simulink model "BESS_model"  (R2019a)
settings: Solver=VariableStepAuto  StartTime=0.0  StopTime=3600*24*3  FixedStep=1  RelTol=1e-3

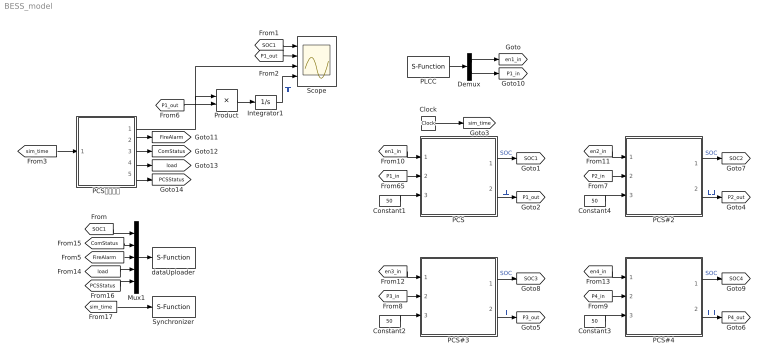
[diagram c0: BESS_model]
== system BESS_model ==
  Clock : Clock
  Constant1 : Constant  Value=50
  Constant2 : Constant  Commented=on  Value=50
  Constant3 : Constant  Commented=on  Value=50
  Constant4 : Constant  Commented=on  Value=50
  Demux : Demux  Outputs=2
  Integrator1 : Integrator
  Mux1 : Mux  Inputs=5
  PCS : Subsystem
  PCS#2 : Subsystem  Commented=on
  PCS#3 : Subsystem  Commented=on
  PCS#4 : Subsystem  Commented=on
  PCS数据生成 : Subsystem
  PLCC : S-Function  FunctionName=modbusCom  SFunctionDeploymentMode=off  EnableBusSupport=off
  Product : Product
  Scope : Scope  NumInputPorts=4
  Synchronizer : S-Function  FunctionName=Synchronizer  SFunctionDeploymentMode=off  EnableBusSupport=off
  dataUploader : S-Function  FunctionName=pcsUpdate  SFunctionDeploymentMode=off  EnableBusSupport=off
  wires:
  [P1_in] -> PCS/2(下发给PCS的遥调)
  Mux1/1 -> dataUploader/1
  PCS/1(SOC) -> [SOC1]  "SOC"
  PCS/2(实际功率) -> [P1_out]  "功率"
  Constant1/1 -> PCS/3(SOC初始值)
  Clock/1 -> [sim_time]
  [P2_in] -> PCS#2/2(下发给PCS的遥调)
  [P3_in] -> PCS#3/2(下发给PCS的遥调)
  [P4_in] -> PCS#4/2(下发给PCS的遥调)
  Constant2/1 -> PCS#3/3(SOC初始值)
  Constant3/1 -> PCS#4/3(SOC初始值)
  Constant4/1 -> PCS#2/3(SOC初始值)
  PCS#2/2(实际功率) -> [P2_out]  "功率"
  PCS#3/2(实际功率) -> [P3_out]  "功率"
  PCS#4/2(实际功率) -> [P4_out]  "功率"
  PCS#2/1(SOC) -> [SOC2]  "SOC"
  PCS#3/1(SOC) -> [SOC3]  "SOC"
  PCS#4/1(SOC) -> [SOC4]  "SOC"
  [en1_in] -> PCS/1(下发给PMS的遥控)
  [en2_in] -> PCS#2/1(下发给PMS的遥控)
  [en3_in] -> PCS#3/1(下发给PMS的遥控)
  [en4_in] -> PCS#4/1(下发给PMS的遥控)
  [SOC1] -> Mux1/1
  PLCC/1 -> Demux/1
  [SOC1] -> Scope/1
  [P1_out] -> Scope/2
  Product/1 -> Integrator1/1
  Integrator1/1 -> Scope/4  "收益"
  [P1_out] -> Product/2
  [ComStatus] -> Mux1/2
  [FireAlarm] -> Mux1/3
  [load] -> Mux1/4
  [PCSStatus] -> Mux1/5
  [sim_time] -> Synchronizer/1
  [sim_time] -> PCS数据生成/1(仿真时间)
  PCS数据生成/2(消防状态) -> [FireAlarm]
  PCS数据生成/3(通信状态) -> [ComStatus]
  PCS数据生成/4(负载) -> [load]
  PCS数据生成/5(PCS状态) -> [PCSStatus]
  PCS数据生成/1(实时电价) -> Scope/3, Product/1
  Demux/1 -> [en1_in]
  Demux/2 -> [P1_in]

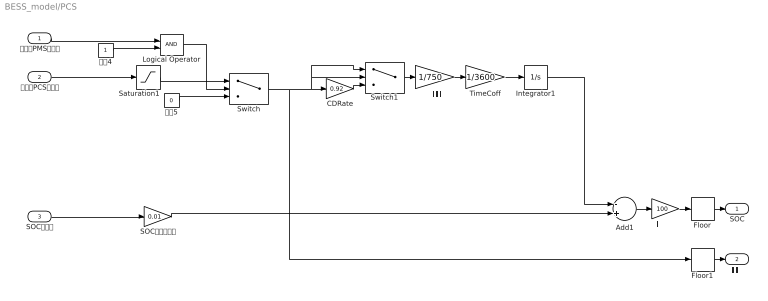
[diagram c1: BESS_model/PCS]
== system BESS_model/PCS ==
  下发给PMS的遥控 : Inport
  下发给PCS的遥调 : Inport  Port=2
  SOC初始值 : Inport  Port=3
  Add1 : Sum  Inputs=-+
  CDRate : Gain  Gain=0.92
  Floor : Rounding
  Floor1 : Rounding
  Integrator1 : Integrator  UpperSaturationLimit=0.5  LowerSaturationLimit=-0.5
  Logical Operator : Logic  AllPortsSameDT=off  OutDataTypeStr=boolean
  SOC转为百分数 : Gain  Gain=0.01
  Saturation1 : Saturate  UpperLimit=500  LowerLimit=-500
  Switch : Switch  Criteria=u2 ~= 0
  Switch1 : Switch  Criteria=u2 > Threshold
  TimeCoff : Gain  Gain=1/3600
  常数4 : Constant
  常数5 : Constant  Value=0
  蓄电池容量 : Gain  Gain=1/750
  转为整数 : Gain  Gain=100
  SOC : Outport  VectorParamsAs1DForOutWhenUnconnected=on
  实际功率 : Outport  Port=2  VectorParamsAs1DForOutWhenUnconnected=on
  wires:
  下发给PCS的遥调/1 -> Saturation1/1
  Switch1/1 -> 蓄电池容量/1
  常数4/1 -> Logical Operator/2
  Logical Operator/1 -> Switch/2
  常数5/1 -> Switch/3
  CDRate/1 -> Switch1/3
  蓄电池容量/1 -> TimeCoff/1
  Switch/1 -> CDRate/1, Switch1/1, Switch1/2, Floor1/1
  TimeCoff/1 -> Integrator1/1
  Integrator1/1 -> Add1/1
  Add1/1 -> 转为整数/1
  下发给PMS的遥控/1 -> Logical Operator/1
  Saturation1/1 -> Switch/1
  SOC初始值/1 -> SOC转为百分数/1
  SOC转为百分数/1 -> Add1/2
  转为整数/1 -> Floor/1
  Floor/1 -> SOC/1
  Floor1/1 -> 实际功率/1

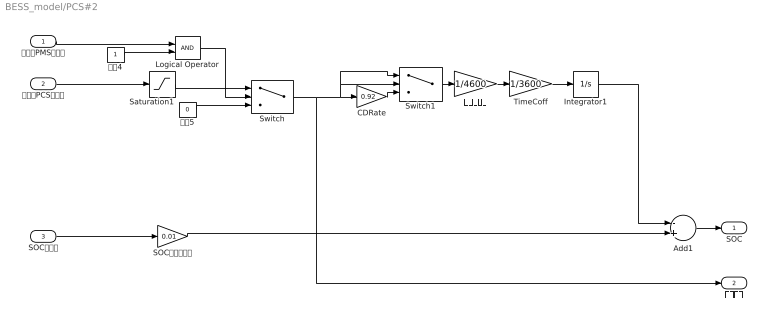
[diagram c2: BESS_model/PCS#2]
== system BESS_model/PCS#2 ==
  下发给PMS的遥控 : Inport
  下发给PCS的遥调 : Inport  Port=2
  SOC初始值 : Inport  Port=3
  Add1 : Sum  Inputs=-+
  CDRate : Gain  Gain=0.92
  Integrator1 : Integrator  UpperSaturationLimit=0.5  LowerSaturationLimit=-0.5
  Logical Operator : Logic  AllPortsSameDT=off  OutDataTypeStr=boolean
  SOC转为百分数 : Gain  Gain=0.01
  Saturation1 : Saturate  UpperLimit=2000  LowerLimit=-2000
  Switch : Switch  Criteria=u2 ~= 0
  Switch1 : Switch  Criteria=u2 > Threshold
  TimeCoff : Gain  Gain=1/3600
  常数4 : Constant
  常数5 : Constant  Value=0
  蓄电池容量 : Gain  Gain=1/4600
  SOC : Outport  VectorParamsAs1DForOutWhenUnconnected=on
  实际功率 : Outport  Port=2  VectorParamsAs1DForOutWhenUnconnected=on
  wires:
  SOC转为百分数/1 -> Add1/2
  SOC初始值/1 -> SOC转为百分数/1
  Saturation1/1 -> Switch/1
  下发给PMS的遥控/1 -> Logical Operator/1
  Add1/1 -> SOC/1
  Integrator1/1 -> Add1/1
  TimeCoff/1 -> Integrator1/1
  Switch/1 -> 实际功率/1, Switch1/2, Switch1/1, CDRate/1
  蓄电池容量/1 -> TimeCoff/1
  CDRate/1 -> Switch1/3
  常数5/1 -> Switch/3
  Logical Operator/1 -> Switch/2
  常数4/1 -> Logical Operator/2
  Switch1/1 -> 蓄电池容量/1
  下发给PCS的遥调/1 -> Saturation1/1

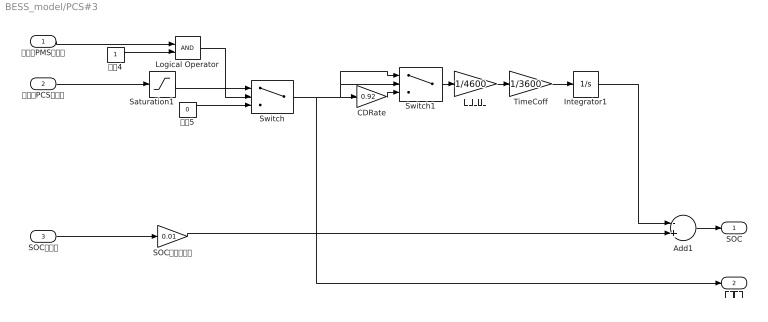
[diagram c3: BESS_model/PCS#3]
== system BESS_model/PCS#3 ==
  下发给PMS的遥控 : Inport
  下发给PCS的遥调 : Inport  Port=2
  SOC初始值 : Inport  Port=3
  Add1 : Sum  Inputs=-+
  CDRate : Gain  Gain=0.92
  Integrator1 : Integrator  UpperSaturationLimit=0.5  LowerSaturationLimit=-0.5
  Logical Operator : Logic  AllPortsSameDT=off  OutDataTypeStr=boolean
  SOC转为百分数 : Gain  Gain=0.01
  Saturation1 : Saturate  UpperLimit=2000  LowerLimit=-2000
  Switch : Switch  Criteria=u2 ~= 0
  Switch1 : Switch  Criteria=u2 > Threshold
  TimeCoff : Gain  Gain=1/3600
  常数4 : Constant
  常数5 : Constant  Value=0
  蓄电池容量 : Gain  Gain=1/4600
  SOC : Outport  VectorParamsAs1DForOutWhenUnconnected=on
  实际功率 : Outport  Port=2  VectorParamsAs1DForOutWhenUnconnected=on
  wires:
  下发给PCS的遥调/1 -> Saturation1/1
  Switch1/1 -> 蓄电池容量/1
  常数4/1 -> Logical Operator/2
  Logical Operator/1 -> Switch/2
  常数5/1 -> Switch/3
  CDRate/1 -> Switch1/3
  蓄电池容量/1 -> TimeCoff/1
  Switch/1 -> CDRate/1, Switch1/1, Switch1/2, 实际功率/1
  TimeCoff/1 -> Integrator1/1
  Integrator1/1 -> Add1/1
  Add1/1 -> SOC/1
  下发给PMS的遥控/1 -> Logical Operator/1
  Saturation1/1 -> Switch/1
  SOC初始值/1 -> SOC转为百分数/1
  SOC转为百分数/1 -> Add1/2

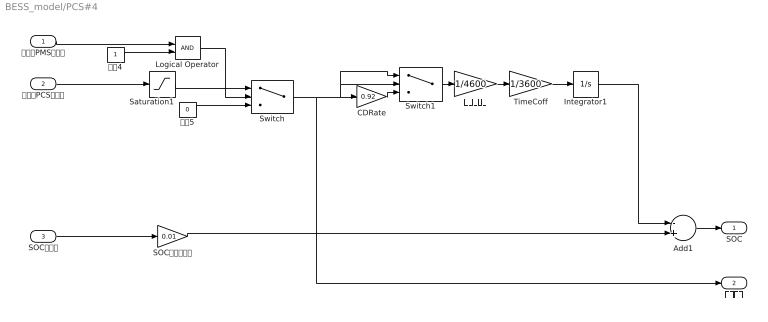
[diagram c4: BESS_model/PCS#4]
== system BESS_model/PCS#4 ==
  下发给PMS的遥控 : Inport
  下发给PCS的遥调 : Inport  Port=2
  SOC初始值 : Inport  Port=3
  Add1 : Sum  Inputs=-+
  CDRate : Gain  Gain=0.92
  Integrator1 : Integrator  UpperSaturationLimit=0.5  LowerSaturationLimit=-0.5
  Logical Operator : Logic  AllPortsSameDT=off  OutDataTypeStr=boolean
  SOC转为百分数 : Gain  Gain=0.01
  Saturation1 : Saturate  UpperLimit=2000  LowerLimit=-2000
  Switch : Switch  Criteria=u2 ~= 0
  Switch1 : Switch  Criteria=u2 > Threshold
  TimeCoff : Gain  Gain=1/3600
  常数4 : Constant
  常数5 : Constant  Value=0
  蓄电池容量 : Gain  Gain=1/4600
  SOC : Outport  VectorParamsAs1DForOutWhenUnconnected=on
  实际功率 : Outport  Port=2  VectorParamsAs1DForOutWhenUnconnected=on
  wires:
  SOC转为百分数/1 -> Add1/2
  SOC初始值/1 -> SOC转为百分数/1
  Saturation1/1 -> Switch/1
  下发给PMS的遥控/1 -> Logical Operator/1
  Add1/1 -> SOC/1
  Integrator1/1 -> Add1/1
  TimeCoff/1 -> Integrator1/1
  Switch/1 -> 实际功率/1, Switch1/2, Switch1/1, CDRate/1
  蓄电池容量/1 -> TimeCoff/1
  CDRate/1 -> Switch1/3
  常数5/1 -> Switch/3
  Logical Operator/1 -> Switch/2
  常数4/1 -> Logical Operator/2
  Switch1/1 -> 蓄电池容量/1
  下发给PCS的遥调/1 -> Saturation1/1

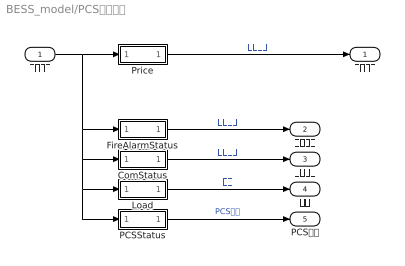
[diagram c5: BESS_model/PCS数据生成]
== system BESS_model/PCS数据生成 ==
  仿真时间 : Inport
  ComStatus : MATLAB Function  TreatAsAtomicUnit=on
  FireAlarmStatus : MATLAB Function  TreatAsAtomicUnit=on
  Load : MATLAB Function  TreatAsAtomicUnit=on
  PCSStatus : MATLAB Function  TreatAsAtomicUnit=on
  Price : MATLAB Function  TreatAsAtomicUnit=on
  实时电价 : Outport
  消防状态 : Outport  Port=2
  通信状态 : Outport  Port=3
  负载 : Outport  Port=4
  PCS状态 : Outport  Port=5
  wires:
  FireAlarmStatus/1(alarm) -> 消防状态/1  "消防状态"
  ComStatus/1(comStatus) -> 通信状态/1  "通信状态"
  仿真时间/1 -> FireAlarmStatus/1(t), PCSStatus/1(t), Load/1(t), ComStatus/1(t), Price/1(t)
  PCSStatus/1(status) -> PCS状态/1  "PCS状态"
  Load/1(lo) -> 负载/1  "负载"
  Price/1(price) -> 实时电价/1  "实时电价"

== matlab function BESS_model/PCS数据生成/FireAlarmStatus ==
function alarm = FireAlarm(t)
% 0正常 1告警 xf_001 
alarm = 0;

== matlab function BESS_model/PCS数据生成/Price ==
function price = get_price(t)
% 输入仿真开始的时间(s)，获得从0点开始计时的实时电价。
tt = t;
while tt >= 24*3600
    tt = tt - 24*3600;
end

% 上海非夏季电价
price = 0.256*(tt>=0 && tt<6*3600) + ...
    0.494*(tt>=6*3600 && tt<8*3600) + ...
    0.843*(tt>=8*3600 && tt<11*3600) + ...
    0.494*(tt>=11*3600 && tt<18*3600) + ...
    0.843*(tt>=18*3600 && tt<21*3600) + ...
    0.494*(tt>=21*3600 && tt<22*3600) + ...
    0.256*(tt>=22*3600 && tt<24*3600);


% % 江苏电价
% price = 1.0347*(tt>=0 && tt<4*3600) + ...
%     0.2589*(tt>=4*3600 && tt<8*3600) + ...
%     1.0347*(tt>=8*3600 && tt<12*3600) + ...
%     0.6068*(tt>=12*3600 && tt<17*3600) + ...
%     1.0347*(tt>=17*3600 && tt<21*3600) + ...
%     0.6068*(tt>=21*3600 && tt<24*3600);

% 测试电价
% price = 0.2589*(tt>=0 && tt<8*3600) + ...
%     1.0347*(tt>=8*3600 && tt<12*3600) + ...
%     0.6068*(tt>=12*3600 && tt<17*3600) + ...
%     1.0347*(tt>=17*3600 && tt<21*3600) + ...
%     0.6068*(tt>=21*3600 && tt<24*3600);

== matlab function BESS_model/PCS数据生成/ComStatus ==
function comStatus = CommuStatus(t)
% 机组通道通讯状态点号 999999001：通信状态；PCS上传
% 电池组pcs结算表通道通讯状态点号 999999002：通信状态；PCS上传
% 消防通道通讯状态点号  999999003：通信状态；PCS上传
% 园区负荷表通道通讯状态点号 999999004：通信状态；PCS上传
% 温控仪通道通讯状态点号 999999005：通信状态；PCS上传
% 万克结算表通道通讯状态点号 999999006：通信状态；PCS上传
% 园区结算表通道通讯状态点号 999999007：通信状态；PCS上传

comStatus = ones(1,7);

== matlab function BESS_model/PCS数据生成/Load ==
function lo = Load(t)
% 负载点号 100090000009：负载大小；PCS上传

lo = 1;

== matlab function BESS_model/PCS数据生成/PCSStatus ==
function status = PCSStatus(t)
% PCS工作状态 10001000310014337：PCS当前工作状态；PCS上传

status = 1;
